VERSION 5.7 ;
BUSBITCHARS "[]" ;
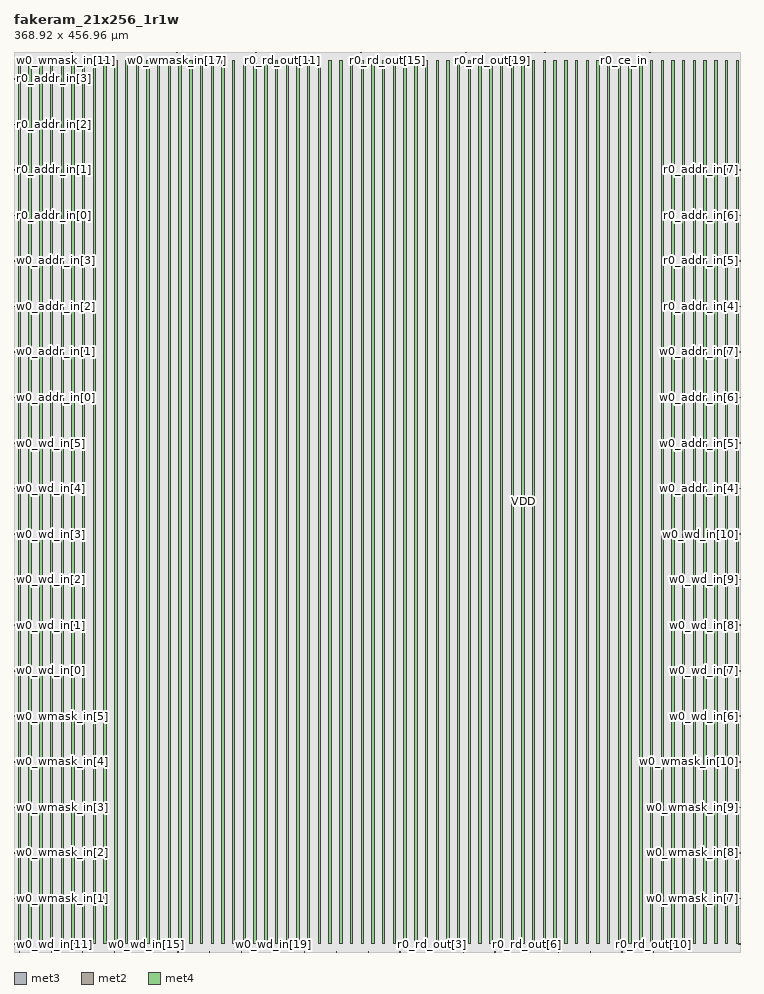
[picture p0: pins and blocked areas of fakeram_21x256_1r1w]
MACRO fakeram_21x256_1r1w
  FOREIGN fakeram_21x256_1r1w 0 0 ;
  SYMMETRY X Y R90 ;
  SIZE 368.920 BY 456.960 ;
  CLASS BLOCK ;
  PIN w0_wmask_in[0]
    DIRECTION INPUT ;
    USE SIGNAL ;
    SHAPE ABUTMENT ;
    PORT
      LAYER met3 ;
      RECT 0.000 3.930 0.900 4.230 ;
    END
  END w0_wmask_in[0]
  PIN w0_wmask_in[1]
    DIRECTION INPUT ;
    USE SIGNAL ;
    SHAPE ABUTMENT ;
    PORT
      LAYER met3 ;
      RECT 0.000 27.050 0.900 27.350 ;
    END
  END w0_wmask_in[1]
  PIN w0_wmask_in[2]
    DIRECTION INPUT ;
    USE SIGNAL ;
    SHAPE ABUTMENT ;
    PORT
      LAYER met3 ;
      RECT 0.000 50.170 0.900 50.470 ;
    END
  END w0_wmask_in[2]
  PIN w0_wmask_in[3]
    DIRECTION INPUT ;
    USE SIGNAL ;
    SHAPE ABUTMENT ;
    PORT
      LAYER met3 ;
      RECT 0.000 73.290 0.900 73.590 ;
    END
  END w0_wmask_in[3]
  PIN w0_wmask_in[4]
    DIRECTION INPUT ;
    USE SIGNAL ;
    SHAPE ABUTMENT ;
    PORT
      LAYER met3 ;
      RECT 0.000 96.410 0.900 96.710 ;
    END
  END w0_wmask_in[4]
  PIN w0_wmask_in[5]
    DIRECTION INPUT ;
    USE SIGNAL ;
    SHAPE ABUTMENT ;
    PORT
      LAYER met3 ;
      RECT 0.000 119.530 0.900 119.830 ;
    END
  END w0_wmask_in[5]
  PIN w0_wmask_in[6]
    DIRECTION INPUT ;
    USE SIGNAL ;
    SHAPE ABUTMENT ;
    PORT
      LAYER met3 ;
      RECT 368.020 3.930 368.920 4.230 ;
    END
  END w0_wmask_in[6]
  PIN w0_wmask_in[7]
    DIRECTION INPUT ;
    USE SIGNAL ;
    SHAPE ABUTMENT ;
    PORT
      LAYER met3 ;
      RECT 368.020 27.050 368.920 27.350 ;
    END
  END w0_wmask_in[7]
  PIN w0_wmask_in[8]
    DIRECTION INPUT ;
    USE SIGNAL ;
    SHAPE ABUTMENT ;
    PORT
      LAYER met3 ;
      RECT 368.020 50.170 368.920 50.470 ;
    END
  END w0_wmask_in[8]
  PIN w0_wmask_in[9]
    DIRECTION INPUT ;
    USE SIGNAL ;
    SHAPE ABUTMENT ;
    PORT
      LAYER met3 ;
      RECT 368.020 73.290 368.920 73.590 ;
    END
  END w0_wmask_in[9]
  PIN w0_wmask_in[10]
    DIRECTION INPUT ;
    USE SIGNAL ;
    SHAPE ABUTMENT ;
    PORT
      LAYER met3 ;
      RECT 368.020 96.410 368.920 96.710 ;
    END
  END w0_wmask_in[10]
  PIN w0_wmask_in[11]
    DIRECTION INPUT ;
    USE SIGNAL ;
    SHAPE ABUTMENT ;
    PORT
      LAYER met2 ;
      RECT 2.690 456.540 2.830 456.960 ;
    END
  END w0_wmask_in[11]
  PIN w0_wmask_in[12]
    DIRECTION INPUT ;
    USE SIGNAL ;
    SHAPE ABUTMENT ;
    PORT
      LAYER met2 ;
      RECT 16.030 456.540 16.170 456.960 ;
    END
  END w0_wmask_in[12]
  PIN w0_wmask_in[13]
    DIRECTION INPUT ;
    USE SIGNAL ;
    SHAPE ABUTMENT ;
    PORT
      LAYER met2 ;
      RECT 29.370 456.540 29.510 456.960 ;
    END
  END w0_wmask_in[13]
  PIN w0_wmask_in[14]
    DIRECTION INPUT ;
    USE SIGNAL ;
    SHAPE ABUTMENT ;
    PORT
      LAYER met2 ;
      RECT 42.710 456.540 42.850 456.960 ;
    END
  END w0_wmask_in[14]
  PIN w0_wmask_in[15]
    DIRECTION INPUT ;
    USE SIGNAL ;
    SHAPE ABUTMENT ;
    PORT
      LAYER met2 ;
      RECT 56.050 456.540 56.190 456.960 ;
    END
  END w0_wmask_in[15]
  PIN w0_wmask_in[16]
    DIRECTION INPUT ;
    USE SIGNAL ;
    SHAPE ABUTMENT ;
    PORT
      LAYER met2 ;
      RECT 69.390 456.540 69.530 456.960 ;
    END
  END w0_wmask_in[16]
  PIN w0_wmask_in[17]
    DIRECTION INPUT ;
    USE SIGNAL ;
    SHAPE ABUTMENT ;
    PORT
      LAYER met2 ;
      RECT 82.730 456.540 82.870 456.960 ;
    END
  END w0_wmask_in[17]
  PIN w0_wmask_in[18]
    DIRECTION INPUT ;
    USE SIGNAL ;
    SHAPE ABUTMENT ;
    PORT
      LAYER met2 ;
      RECT 96.070 456.540 96.210 456.960 ;
    END
  END w0_wmask_in[18]
  PIN w0_wmask_in[19]
    DIRECTION INPUT ;
    USE SIGNAL ;
    SHAPE ABUTMENT ;
    PORT
      LAYER met2 ;
      RECT 109.410 456.540 109.550 456.960 ;
    END
  END w0_wmask_in[19]
  PIN w0_wmask_in[20]
    DIRECTION INPUT ;
    USE SIGNAL ;
    SHAPE ABUTMENT ;
    PORT
      LAYER met2 ;
      RECT 122.750 456.540 122.890 456.960 ;
    END
  END w0_wmask_in[20]
  PIN w0_wd_in[0]
    DIRECTION INPUT ;
    USE SIGNAL ;
    SHAPE ABUTMENT ;
    PORT
      LAYER met3 ;
      RECT 0.000 142.650 0.900 142.950 ;
    END
  END w0_wd_in[0]
  PIN w0_wd_in[1]
    DIRECTION INPUT ;
    USE SIGNAL ;
    SHAPE ABUTMENT ;
    PORT
      LAYER met3 ;
      RECT 0.000 165.770 0.900 166.070 ;
    END
  END w0_wd_in[1]
  PIN w0_wd_in[2]
    DIRECTION INPUT ;
    USE SIGNAL ;
    SHAPE ABUTMENT ;
    PORT
      LAYER met3 ;
      RECT 0.000 188.890 0.900 189.190 ;
    END
  END w0_wd_in[2]
  PIN w0_wd_in[3]
    DIRECTION INPUT ;
    USE SIGNAL ;
    SHAPE ABUTMENT ;
    PORT
      LAYER met3 ;
      RECT 0.000 212.010 0.900 212.310 ;
    END
  END w0_wd_in[3]
  PIN w0_wd_in[4]
    DIRECTION INPUT ;
    USE SIGNAL ;
    SHAPE ABUTMENT ;
    PORT
      LAYER met3 ;
      RECT 0.000 235.130 0.900 235.430 ;
    END
  END w0_wd_in[4]
  PIN w0_wd_in[5]
    DIRECTION INPUT ;
    USE SIGNAL ;
    SHAPE ABUTMENT ;
    PORT
      LAYER met3 ;
      RECT 0.000 258.250 0.900 258.550 ;
    END
  END w0_wd_in[5]
  PIN w0_wd_in[6]
    DIRECTION INPUT ;
    USE SIGNAL ;
    SHAPE ABUTMENT ;
    PORT
      LAYER met3 ;
      RECT 368.020 119.530 368.920 119.830 ;
    END
  END w0_wd_in[6]
  PIN w0_wd_in[7]
    DIRECTION INPUT ;
    USE SIGNAL ;
    SHAPE ABUTMENT ;
    PORT
      LAYER met3 ;
      RECT 368.020 142.650 368.920 142.950 ;
    END
  END w0_wd_in[7]
  PIN w0_wd_in[8]
    DIRECTION INPUT ;
    USE SIGNAL ;
    SHAPE ABUTMENT ;
    PORT
      LAYER met3 ;
      RECT 368.020 165.770 368.920 166.070 ;
    END
  END w0_wd_in[8]
  PIN w0_wd_in[9]
    DIRECTION INPUT ;
    USE SIGNAL ;
    SHAPE ABUTMENT ;
    PORT
      LAYER met3 ;
      RECT 368.020 188.890 368.920 189.190 ;
    END
  END w0_wd_in[9]
  PIN w0_wd_in[10]
    DIRECTION INPUT ;
    USE SIGNAL ;
    SHAPE ABUTMENT ;
    PORT
      LAYER met3 ;
      RECT 368.020 212.010 368.920 212.310 ;
    END
  END w0_wd_in[10]
  PIN w0_wd_in[11]
    DIRECTION INPUT ;
    USE SIGNAL ;
    SHAPE ABUTMENT ;
    PORT
      LAYER met2 ;
      RECT 2.690 0.000 2.830 0.420 ;
    END
  END w0_wd_in[11]
  PIN w0_wd_in[12]
    DIRECTION INPUT ;
    USE SIGNAL ;
    SHAPE ABUTMENT ;
    PORT
      LAYER met2 ;
      RECT 18.790 0.000 18.930 0.420 ;
    END
  END w0_wd_in[12]
  PIN w0_wd_in[13]
    DIRECTION INPUT ;
    USE SIGNAL ;
    SHAPE ABUTMENT ;
    PORT
      LAYER met2 ;
      RECT 34.890 0.000 35.030 0.420 ;
    END
  END w0_wd_in[13]
  PIN w0_wd_in[14]
    DIRECTION INPUT ;
    USE SIGNAL ;
    SHAPE ABUTMENT ;
    PORT
      LAYER met2 ;
      RECT 50.990 0.000 51.130 0.420 ;
    END
  END w0_wd_in[14]
  PIN w0_wd_in[15]
    DIRECTION INPUT ;
    USE SIGNAL ;
    SHAPE ABUTMENT ;
    PORT
      LAYER met2 ;
      RECT 67.090 0.000 67.230 0.420 ;
    END
  END w0_wd_in[15]
  PIN w0_wd_in[16]
    DIRECTION INPUT ;
    USE SIGNAL ;
    SHAPE ABUTMENT ;
    PORT
      LAYER met2 ;
      RECT 83.190 0.000 83.330 0.420 ;
    END
  END w0_wd_in[16]
  PIN w0_wd_in[17]
    DIRECTION INPUT ;
    USE SIGNAL ;
    SHAPE ABUTMENT ;
    PORT
      LAYER met2 ;
      RECT 99.290 0.000 99.430 0.420 ;
    END
  END w0_wd_in[17]
  PIN w0_wd_in[18]
    DIRECTION INPUT ;
    USE SIGNAL ;
    SHAPE ABUTMENT ;
    PORT
      LAYER met2 ;
      RECT 115.390 0.000 115.530 0.420 ;
    END
  END w0_wd_in[18]
  PIN w0_wd_in[19]
    DIRECTION INPUT ;
    USE SIGNAL ;
    SHAPE ABUTMENT ;
    PORT
      LAYER met2 ;
      RECT 131.490 0.000 131.630 0.420 ;
    END
  END w0_wd_in[19]
  PIN w0_wd_in[20]
    DIRECTION INPUT ;
    USE SIGNAL ;
    SHAPE ABUTMENT ;
    PORT
      LAYER met2 ;
      RECT 147.590 0.000 147.730 0.420 ;
    END
  END w0_wd_in[20]
  PIN r0_rd_out[0]
    DIRECTION OUTPUT ;
    USE SIGNAL ;
    SHAPE ABUTMENT ;
    PORT
      LAYER met2 ;
      RECT 163.690 0.000 163.830 0.420 ;
    END
  END r0_rd_out[0]
  PIN r0_rd_out[1]
    DIRECTION OUTPUT ;
    USE SIGNAL ;
    SHAPE ABUTMENT ;
    PORT
      LAYER met2 ;
      RECT 179.790 0.000 179.930 0.420 ;
    END
  END r0_rd_out[1]
  PIN r0_rd_out[2]
    DIRECTION OUTPUT ;
    USE SIGNAL ;
    SHAPE ABUTMENT ;
    PORT
      LAYER met2 ;
      RECT 195.890 0.000 196.030 0.420 ;
    END
  END r0_rd_out[2]
  PIN r0_rd_out[3]
    DIRECTION OUTPUT ;
    USE SIGNAL ;
    SHAPE ABUTMENT ;
    PORT
      LAYER met2 ;
      RECT 211.990 0.000 212.130 0.420 ;
    END
  END r0_rd_out[3]
  PIN r0_rd_out[4]
    DIRECTION OUTPUT ;
    USE SIGNAL ;
    SHAPE ABUTMENT ;
    PORT
      LAYER met2 ;
      RECT 228.090 0.000 228.230 0.420 ;
    END
  END r0_rd_out[4]
  PIN r0_rd_out[5]
    DIRECTION OUTPUT ;
    USE SIGNAL ;
    SHAPE ABUTMENT ;
    PORT
      LAYER met2 ;
      RECT 244.190 0.000 244.330 0.420 ;
    END
  END r0_rd_out[5]
  PIN r0_rd_out[6]
    DIRECTION OUTPUT ;
    USE SIGNAL ;
    SHAPE ABUTMENT ;
    PORT
      LAYER met2 ;
      RECT 260.290 0.000 260.430 0.420 ;
    END
  END r0_rd_out[6]
  PIN r0_rd_out[7]
    DIRECTION OUTPUT ;
    USE SIGNAL ;
    SHAPE ABUTMENT ;
    PORT
      LAYER met2 ;
      RECT 276.390 0.000 276.530 0.420 ;
    END
  END r0_rd_out[7]
  PIN r0_rd_out[8]
    DIRECTION OUTPUT ;
    USE SIGNAL ;
    SHAPE ABUTMENT ;
    PORT
      LAYER met2 ;
      RECT 292.490 0.000 292.630 0.420 ;
    END
  END r0_rd_out[8]
  PIN r0_rd_out[9]
    DIRECTION OUTPUT ;
    USE SIGNAL ;
    SHAPE ABUTMENT ;
    PORT
      LAYER met2 ;
      RECT 308.590 0.000 308.730 0.420 ;
    END
  END r0_rd_out[9]
  PIN r0_rd_out[10]
    DIRECTION OUTPUT ;
    USE SIGNAL ;
    SHAPE ABUTMENT ;
    PORT
      LAYER met2 ;
      RECT 324.690 0.000 324.830 0.420 ;
    END
  END r0_rd_out[10]
  PIN r0_rd_out[11]
    DIRECTION OUTPUT ;
    USE SIGNAL ;
    SHAPE ABUTMENT ;
    PORT
      LAYER met2 ;
      RECT 136.090 456.540 136.230 456.960 ;
    END
  END r0_rd_out[11]
  PIN r0_rd_out[12]
    DIRECTION OUTPUT ;
    USE SIGNAL ;
    SHAPE ABUTMENT ;
    PORT
      LAYER met2 ;
      RECT 149.430 456.540 149.570 456.960 ;
    END
  END r0_rd_out[12]
  PIN r0_rd_out[13]
    DIRECTION OUTPUT ;
    USE SIGNAL ;
    SHAPE ABUTMENT ;
    PORT
      LAYER met2 ;
      RECT 162.770 456.540 162.910 456.960 ;
    END
  END r0_rd_out[13]
  PIN r0_rd_out[14]
    DIRECTION OUTPUT ;
    USE SIGNAL ;
    SHAPE ABUTMENT ;
    PORT
      LAYER met2 ;
      RECT 176.110 456.540 176.250 456.960 ;
    END
  END r0_rd_out[14]
  PIN r0_rd_out[15]
    DIRECTION OUTPUT ;
    USE SIGNAL ;
    SHAPE ABUTMENT ;
    PORT
      LAYER met2 ;
      RECT 189.450 456.540 189.590 456.960 ;
    END
  END r0_rd_out[15]
  PIN r0_rd_out[16]
    DIRECTION OUTPUT ;
    USE SIGNAL ;
    SHAPE ABUTMENT ;
    PORT
      LAYER met2 ;
      RECT 202.790 456.540 202.930 456.960 ;
    END
  END r0_rd_out[16]
  PIN r0_rd_out[17]
    DIRECTION OUTPUT ;
    USE SIGNAL ;
    SHAPE ABUTMENT ;
    PORT
      LAYER met2 ;
      RECT 216.130 456.540 216.270 456.960 ;
    END
  END r0_rd_out[17]
  PIN r0_rd_out[18]
    DIRECTION OUTPUT ;
    USE SIGNAL ;
    SHAPE ABUTMENT ;
    PORT
      LAYER met2 ;
      RECT 229.470 456.540 229.610 456.960 ;
    END
  END r0_rd_out[18]
  PIN r0_rd_out[19]
    DIRECTION OUTPUT ;
    USE SIGNAL ;
    SHAPE ABUTMENT ;
    PORT
      LAYER met2 ;
      RECT 242.810 456.540 242.950 456.960 ;
    END
  END r0_rd_out[19]
  PIN r0_rd_out[20]
    DIRECTION OUTPUT ;
    USE SIGNAL ;
    SHAPE ABUTMENT ;
    PORT
      LAYER met2 ;
      RECT 256.150 456.540 256.290 456.960 ;
    END
  END r0_rd_out[20]
  PIN w0_addr_in[0]
    DIRECTION INPUT ;
    USE SIGNAL ;
    SHAPE ABUTMENT ;
    PORT
      LAYER met3 ;
      RECT 0.000 281.370 0.900 281.670 ;
    END
  END w0_addr_in[0]
  PIN w0_addr_in[1]
    DIRECTION INPUT ;
    USE SIGNAL ;
    SHAPE ABUTMENT ;
    PORT
      LAYER met3 ;
      RECT 0.000 304.490 0.900 304.790 ;
    END
  END w0_addr_in[1]
  PIN w0_addr_in[2]
    DIRECTION INPUT ;
    USE SIGNAL ;
    SHAPE ABUTMENT ;
    PORT
      LAYER met3 ;
      RECT 0.000 327.610 0.900 327.910 ;
    END
  END w0_addr_in[2]
  PIN w0_addr_in[3]
    DIRECTION INPUT ;
    USE SIGNAL ;
    SHAPE ABUTMENT ;
    PORT
      LAYER met3 ;
      RECT 0.000 350.730 0.900 351.030 ;
    END
  END w0_addr_in[3]
  PIN w0_addr_in[4]
    DIRECTION INPUT ;
    USE SIGNAL ;
    SHAPE ABUTMENT ;
    PORT
      LAYER met3 ;
      RECT 368.020 235.130 368.920 235.430 ;
    END
  END w0_addr_in[4]
  PIN w0_addr_in[5]
    DIRECTION INPUT ;
    USE SIGNAL ;
    SHAPE ABUTMENT ;
    PORT
      LAYER met3 ;
      RECT 368.020 258.250 368.920 258.550 ;
    END
  END w0_addr_in[5]
  PIN w0_addr_in[6]
    DIRECTION INPUT ;
    USE SIGNAL ;
    SHAPE ABUTMENT ;
    PORT
      LAYER met3 ;
      RECT 368.020 281.370 368.920 281.670 ;
    END
  END w0_addr_in[6]
  PIN w0_addr_in[7]
    DIRECTION INPUT ;
    USE SIGNAL ;
    SHAPE ABUTMENT ;
    PORT
      LAYER met3 ;
      RECT 368.020 304.490 368.920 304.790 ;
    END
  END w0_addr_in[7]
  PIN r0_addr_in[0]
    DIRECTION INPUT ;
    USE SIGNAL ;
    SHAPE ABUTMENT ;
    PORT
      LAYER met3 ;
      RECT 0.000 373.850 0.900 374.150 ;
    END
  END r0_addr_in[0]
  PIN r0_addr_in[1]
    DIRECTION INPUT ;
    USE SIGNAL ;
    SHAPE ABUTMENT ;
    PORT
      LAYER met3 ;
      RECT 0.000 396.970 0.900 397.270 ;
    END
  END r0_addr_in[1]
  PIN r0_addr_in[2]
    DIRECTION INPUT ;
    USE SIGNAL ;
    SHAPE ABUTMENT ;
    PORT
      LAYER met3 ;
      RECT 0.000 420.090 0.900 420.390 ;
    END
  END r0_addr_in[2]
  PIN r0_addr_in[3]
    DIRECTION INPUT ;
    USE SIGNAL ;
    SHAPE ABUTMENT ;
    PORT
      LAYER met3 ;
      RECT 0.000 443.210 0.900 443.510 ;
    END
  END r0_addr_in[3]
  PIN r0_addr_in[4]
    DIRECTION INPUT ;
    USE SIGNAL ;
    SHAPE ABUTMENT ;
    PORT
      LAYER met3 ;
      RECT 368.020 327.610 368.920 327.910 ;
    END
  END r0_addr_in[4]
  PIN r0_addr_in[5]
    DIRECTION INPUT ;
    USE SIGNAL ;
    SHAPE ABUTMENT ;
    PORT
      LAYER met3 ;
      RECT 368.020 350.730 368.920 351.030 ;
    END
  END r0_addr_in[5]
  PIN r0_addr_in[6]
    DIRECTION INPUT ;
    USE SIGNAL ;
    SHAPE ABUTMENT ;
    PORT
      LAYER met3 ;
      RECT 368.020 373.850 368.920 374.150 ;
    END
  END r0_addr_in[6]
  PIN r0_addr_in[7]
    DIRECTION INPUT ;
    USE SIGNAL ;
    SHAPE ABUTMENT ;
    PORT
      LAYER met3 ;
      RECT 368.020 396.970 368.920 397.270 ;
    END
  END r0_addr_in[7]
  PIN w0_we_in
    DIRECTION INPUT ;
    USE SIGNAL ;
    SHAPE ABUTMENT ;
    PORT
      LAYER met2 ;
      RECT 269.490 456.540 269.630 456.960 ;
    END
  END w0_we_in
  PIN w0_ce_in
    DIRECTION INPUT ;
    USE SIGNAL ;
    SHAPE ABUTMENT ;
    PORT
      LAYER met2 ;
      RECT 282.830 456.540 282.970 456.960 ;
    END
  END w0_ce_in
  PIN w0_clk
    DIRECTION INPUT ;
    USE SIGNAL ;
    SHAPE ABUTMENT ;
    PORT
      LAYER met2 ;
      RECT 296.170 456.540 296.310 456.960 ;
    END
  END w0_clk
  PIN r0_ce_in
    DIRECTION INPUT ;
    USE SIGNAL ;
    SHAPE ABUTMENT ;
    PORT
      LAYER met2 ;
      RECT 309.510 456.540 309.650 456.960 ;
    END
  END r0_ce_in
  PIN r0_clk
    DIRECTION INPUT ;
    USE SIGNAL ;
    SHAPE ABUTMENT ;
    PORT
      LAYER met2 ;
      RECT 322.850 456.540 322.990 456.960 ;
    END
  END r0_clk
  PIN VSS
    DIRECTION INOUT ;
    USE GROUND ;
    PORT
      LAYER met4 ;
      RECT 2.160 4.080 3.360 452.880 ;
      RECT 13.040 4.080 14.240 452.880 ;
      RECT 23.920 4.080 25.120 452.880 ;
      RECT 34.800 4.080 36.000 452.880 ;
      RECT 45.680 4.080 46.880 452.880 ;
      RECT 56.560 4.080 57.760 452.880 ;
      RECT 67.440 4.080 68.640 452.880 ;
      RECT 78.320 4.080 79.520 452.880 ;
      RECT 89.200 4.080 90.400 452.880 ;
      RECT 100.080 4.080 101.280 452.880 ;
      RECT 110.960 4.080 112.160 452.880 ;
      RECT 121.840 4.080 123.040 452.880 ;
      RECT 132.720 4.080 133.920 452.880 ;
      RECT 143.600 4.080 144.800 452.880 ;
      RECT 154.480 4.080 155.680 452.880 ;
      RECT 165.360 4.080 166.560 452.880 ;
      RECT 176.240 4.080 177.440 452.880 ;
      RECT 187.120 4.080 188.320 452.880 ;
      RECT 198.000 4.080 199.200 452.880 ;
      RECT 208.880 4.080 210.080 452.880 ;
      RECT 219.760 4.080 220.960 452.880 ;
      RECT 230.640 4.080 231.840 452.880 ;
      RECT 241.520 4.080 242.720 452.880 ;
      RECT 252.400 4.080 253.600 452.880 ;
      RECT 263.280 4.080 264.480 452.880 ;
      RECT 274.160 4.080 275.360 452.880 ;
      RECT 285.040 4.080 286.240 452.880 ;
      RECT 295.920 4.080 297.120 452.880 ;
      RECT 306.800 4.080 308.000 452.880 ;
      RECT 317.680 4.080 318.880 452.880 ;
      RECT 328.560 4.080 329.760 452.880 ;
      RECT 339.440 4.080 340.640 452.880 ;
      RECT 350.320 4.080 351.520 452.880 ;
      RECT 361.200 4.080 362.400 452.880 ;
    END
  END VSS
  PIN VDD
    DIRECTION INOUT ;
    USE POWER ;
    PORT
      LAYER met4 ;
      RECT 7.600 4.080 8.800 452.880 ;
      RECT 18.480 4.080 19.680 452.880 ;
      RECT 29.360 4.080 30.560 452.880 ;
      RECT 40.240 4.080 41.440 452.880 ;
      RECT 51.120 4.080 52.320 452.880 ;
      RECT 62.000 4.080 63.200 452.880 ;
      RECT 72.880 4.080 74.080 452.880 ;
      RECT 83.760 4.080 84.960 452.880 ;
      RECT 94.640 4.080 95.840 452.880 ;
      RECT 105.520 4.080 106.720 452.880 ;
      RECT 116.400 4.080 117.600 452.880 ;
      RECT 127.280 4.080 128.480 452.880 ;
      RECT 138.160 4.080 139.360 452.880 ;
      RECT 149.040 4.080 150.240 452.880 ;
      RECT 159.920 4.080 161.120 452.880 ;
      RECT 170.800 4.080 172.000 452.880 ;
      RECT 181.680 4.080 182.880 452.880 ;
      RECT 192.560 4.080 193.760 452.880 ;
      RECT 203.440 4.080 204.640 452.880 ;
      RECT 214.320 4.080 215.520 452.880 ;
      RECT 225.200 4.080 226.400 452.880 ;
      RECT 236.080 4.080 237.280 452.880 ;
      RECT 246.960 4.080 248.160 452.880 ;
      RECT 257.840 4.080 259.040 452.880 ;
      RECT 268.720 4.080 269.920 452.880 ;
      RECT 279.600 4.080 280.800 452.880 ;
      RECT 290.480 4.080 291.680 452.880 ;
      RECT 301.360 4.080 302.560 452.880 ;
      RECT 312.240 4.080 313.440 452.880 ;
      RECT 323.120 4.080 324.320 452.880 ;
      RECT 334.000 4.080 335.200 452.880 ;
      RECT 344.880 4.080 346.080 452.880 ;
      RECT 355.760 4.080 356.960 452.880 ;
      RECT 366.640 4.080 367.840 452.880 ;
    END
  END VDD
  OBS
    LAYER met1 ;
    RECT 0 0 368.920 456.960 ;
    LAYER met2 ;
    RECT 0 0 368.920 456.960 ;
    LAYER met3 ;
    RECT 0 0 368.920 456.960 ;
    LAYER met4 ;
    RECT 0 0 368.920 456.960 ;
  END
END fakeram_21x256_1r1w

END LIBRARY
